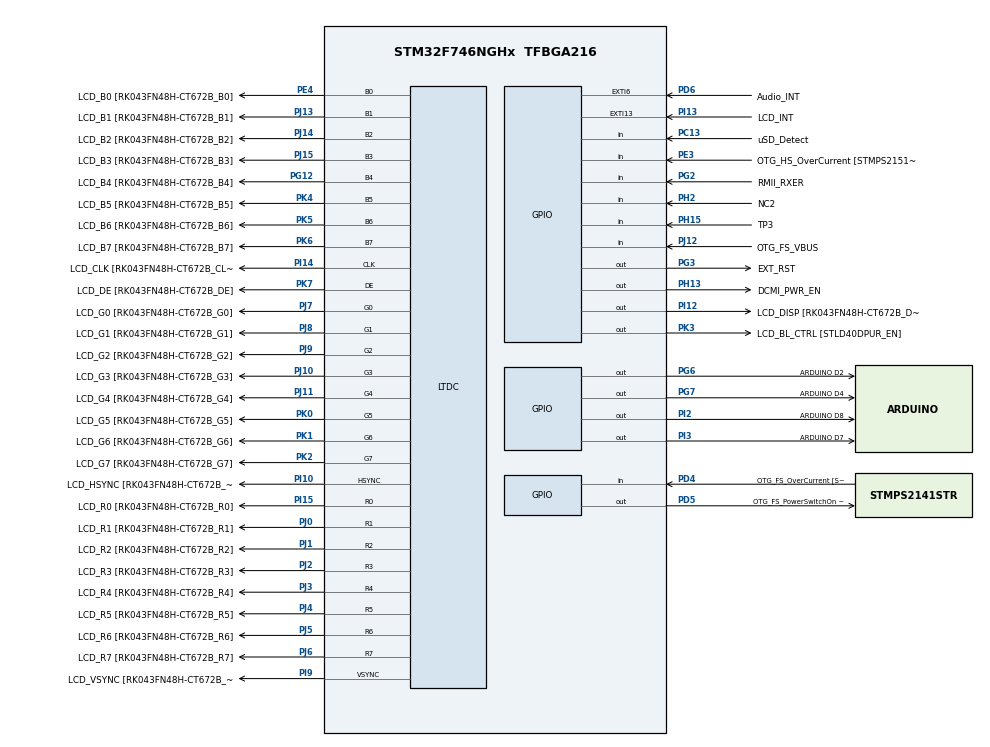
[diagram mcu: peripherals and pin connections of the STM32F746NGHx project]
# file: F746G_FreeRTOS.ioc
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FREERTOS.Tasks01=defaultTask,0,128,StartDefaultTask,Default,NULL
FREERTOS.configUSE_TIMERS=1
Mcu.Family=STM32F7
Mcu.Name=STM32F746NGHx
Mcu.Package=TFBGA216
NVIC.PriorityGroup=NVIC_PRIORITYGROUP_4
NVIC.TIM6_DAC_IRQn=true\:0\:0\:false\:false\:true\:false\:false
NVIC.TimeBase=TIM6_DAC_IRQn
NVIC.TimeBaseIP=TIM6
PA0/WKUP.GPIO_Label=ARDUINO A0
PA0/WKUP.GPIO_Mode=GPIO_MODE_ANALOG
PA0/WKUP.GPIO_PuPd=GPIO_NOPULL
PA0/WKUP.Signal=ADCx_IN0
PA1.GPIO_Label=RMII_REF_CLK [LAN8742A-CZ-TR_REFCLK0]
PA1.Signal=ETH_REF_CLK
PA10.GPIO_Label=OTG_FS_ID
PA10.Signal=USB_OTG_FS_ID
PA11.GPIO_Label=OTG_FS_N
PA11.Signal=USB_OTG_FS_DM
PA12.GPIO_Label=OTG_FS_P
PA12.Signal=USB_OTG_FS_DP
PA13.GPIO_Label=SWDIO
PA13.Signal=SYS_JTMS-SWDIO
PA14.GPIO_Label=SWCLK
PA14.Signal=SYS_JTCK-SWCLK
PA15.GPIO_Label=ARDUINO PWM/D9
PA15.GPIO_ModeDefaultPP=GPIO_MODE_AF_PP
PA15.GPIO_PuPd=GPIO_NOPULL
PA15.GPIO_Speed=GPIO_SPEED_FREQ_LOW
PA15.Signal=S_TIM2_CH1_ETR
PA2.GPIO_Label=RMII_MDIO [LAN8742A-CZ-TR_MDIO]
PA2.Signal=ETH_MDIO
PA3.GPIO_Label=ULPI_D0 [USB3320C-EZK_D0]
PA3.Signal=USB_OTG_HS_ULPI_D0
PA4.GPIO_Label=DCMI_HSYNC
PA4.Signal=DCMI_HSYNC
PA5.GPIO_Label=ULPI_CLK [USB3320C-EZK_CLKOUT]
PA5.Signal=USB_OTG_HS_ULPI_CK
PA6.Signal=DCMI_PIXCLK
PA7.GPIO_Label=RMII_CRS_DV [LAN8742A-CZ-TR_CRS_DV]
PA7.Signal=ETH_CRS_DV
PA8.GPIO_Label=ARDUINO PWM/D10
PA8.GPIO_ModeDefaultPP=GPIO_MODE_AF_PP
PA8.GPIO_PuPd=GPIO_NOPULL
PA8.GPIO_Speed=GPIO_SPEED_FREQ_LOW
PA8.Signal=S_TIM1_CH1
PA9.GPIO_Label=VCP_TX [STM32F103CBT6_PA3]
PA9.GPIO_Mode=GPIO_MODE_AF_PP
PA9.GPIO_PuPd=GPIO_NOPULL
PA9.GPIO_Speed=GPIO_SPEED_FREQ_LOW
PA9.Signal=USART1_TX
PB0.GPIO_Label=ULPI_D1 [USB3320C-EZK_D1]
PB0.Signal=USB_OTG_HS_ULPI_D1
PB1.GPIO_Label=ULPI_D2 [USB3320C-EZK_D2]
PB1.Signal=USB_OTG_HS_ULPI_D2
PB10.GPIO_Label=ULPI_D3 [USB3320C-EZK_D3]
PB10.Signal=USB_OTG_HS_ULPI_D3
PB11.GPIO_Label=ULPI_D4 [USB3320C-EZK_D4]
PB11.Signal=USB_OTG_HS_ULPI_D4
PB12.GPIO_Label=ULPI_D5 [USB3320C-EZK_D5]
PB12.Signal=USB_OTG_HS_ULPI_D5
PB13.GPIO_Label=ULPI_D6 [USB3320C-EZK_D6]
PB13.Signal=USB_OTG_HS_ULPI_D6
PB14.GPIO_Label=ARDUINO MISO/D12
PB14.GPIO_Mode=GPIO_MODE_AF_PP
PB14.GPIO_PuPd=GPIO_NOPULL
PB14.GPIO_Speed=GPIO_SPEED_FREQ_LOW
PB14.Signal=SPI2_MISO
PB15.GPIO_Label=ARDUINO MOSI/PWM/D11
PB15.GPIO_Mode=GPIO_MODE_AF_PP
PB15.GPIO_PuPd=GPIO_NOPULL
PB15.GPIO_Speed=GPIO_SPEED_FREQ_LOW
PB15.Signal=SPI2_MOSI
PB2.Signal=QUADSPI_CLK
PB3.GPIO_Label=SWO
PB3.Signal=SYS_JTDO-SWO
PB4.GPIO_Label=ARDUINO PWM/D3
PB4.GPIO_ModeDefaultPP=GPIO_MODE_AF_PP
PB4.GPIO_PuPd=GPIO_NOPULL
PB4.GPIO_Speed=GPIO_SPEED_FREQ_LOW
PB4.Signal=S_TIM3_CH1
PB5.GPIO_Label=ULPI_D7 [USB3320C-EZK_D7]
PB5.Signal=USB_OTG_HS_ULPI_D7
PB6.GPIO_Label=QSPI_NCS [N25Q128A13EF840E_S]
PB6.Signal=QUADSPI_BK1_NCS
PB7.GPIO_Label=VCP_RX [STM32F103CBT6_PA2]
PB7.GPIO_Mode=GPIO_MODE_AF_PP
PB7.GPIO_PuPd=GPIO_NOPULL
PB7.GPIO_Speed=GPIO_SPEED_FREQ_LOW
PB7.Signal=USART1_RX
PB8.GPIO_Label=ARDUINO SCL/D15
PB8.GPIO_Mode=GPIO_MODE_AF_OD
PB8.GPIO_PuPd=GPIO_NOPULL
PB8.GPIO_Speed=GPIO_SPEED_FREQ_LOW
PB8.Signal=I2C1_SCL
PB9.GPIO_Label=ARDUINO SDA/D14
PB9.GPIO_Mode=GPIO_MODE_AF_OD
PB9.GPIO_PuPd=GPIO_NOPULL
PB9.GPIO_Speed=GPIO_SPEED_FREQ_LOW
PB9.Signal=I2C1_SDA
PC0.GPIO_Label=ULPI_STP [USB3320C-EZK_STP]
PC0.Signal=USB_OTG_HS_ULPI_STP
PC1.GPIO_Label=RMII_MDC [LAN8742A-CZ-TR_MDC]
PC1.Signal=ETH_MDC
PC10.GPIO_Label=SDMMC_D2
PC10.Signal=SDMMC1_D2
PC11.GPIO_Label=SDMMC_D3
PC11.Signal=SDMMC1_D3
PC12.GPIO_Label=SDMMC_CK
PC12.Signal=SDMMC1_CK
PC13.GPIO_Label=uSD_Detect
PC13.Signal=GPIO_Input
PC14/OSC32_IN.GPIO_Label=RCC_OSC32_IN
PC14/OSC32_IN.Signal=RCC_OSC32_IN
PC15/OSC32_OUT.GPIO_Label=RCC_OSC32_OUT
PC15/OSC32_OUT.Signal=RCC_OSC32_OUT
PC2.GPIO_Label=ULPI_DIR [USB3320C-EZK_DIR]
PC2.Signal=USB_OTG_HS_ULPI_DIR
PC3.GPIO_Label=FMC_SDCKE0 [MT48LC4M32B2B5-6A_CKE]
PC3.Signal=FMC_SDCKE0
PC4.GPIO_Label=RMII_RXD0 [LAN8742A-CZ-TR_RXD0]
PC4.Signal=ETH_RXD0
PC5.GPIO_Label=RMII_RXD1 [LAN8742A-CZ-TR_RXD1]
PC5.Signal=ETH_RXD1
PC6.GPIO_Label=ARDUINO TX/D1
PC6.Signal=USART6_TX
PC7.GPIO_Label=ARDUINO RX/D0
PC7.Signal=USART6_RX
PC8.Signal=SDMMC1_D0
PC9.Signal=SDMMC1_D1
PD0.GPIO_Label=FMC_D2 [MT48LC4M32B2B5-6A_DQ2]
PD0.Signal=FMC_D2_DA2
PD1.GPIO_Label=FMC_D3 [MT48LC4M32B2B5-6A_DQ3]
PD1.Signal=FMC_D3_DA3
PD10.GPIO_Label=FMC_D15 [MT48LC4M32B2B5-6A_DQ15]
PD10.Signal=FMC_D15_DA15
PD11.GPIO_Label=QSPI_D0 [N25Q128A13EF840E_DQ0]
PD11.Signal=QUADSPI_BK1_IO0
PD12.GPIO_Label=QSPI_D1 [N25Q128A13EF840E_DQ1]
PD12.Signal=QUADSPI_BK1_IO1
PD13.GPIO_Label=QSPI_D3 [N25Q128A13EF840E_DQ3]
PD13.Signal=QUADSPI_BK1_IO3
PD14.GPIO_Label=FMC_D0 [MT48LC4M32B2B5-6A_DQ0]
PD14.Signal=FMC_D0_DA0
PD15.GPIO_Label=FMC_D1 [MT48LC4M32B2B5-6A_DQ1]
PD15.Signal=FMC_D1_DA1
PD2.GPIO_Label=SDMMC_D0
PD2.Signal=SDMMC1_CMD
PD3.GPIO_Label=DCMI_D5
PD3.Signal=DCMI_D5
PD4.GPIO_Label=OTG_FS_OverCurrent [STMPS2141STR_Fault]
PD4.Signal=GPIO_Input
PD5.GPIO_Label=OTG_FS_PowerSwitchOn [STMPS2141STR_EN]
PD5.PinState=GPIO_PIN_SET
PD5.Signal=GPIO_Output
PD6.GPIO_Label=Audio_INT
PD6.GPIO_ModeDefaultEXTI=GPIO_MODE_EVT_RISING
PD6.Signal=GPXTI6
PD7.GPIO_Label=SPDIF_RX0 [74LVC1G04SE_4]
PD7.Signal=SPDIFRX_IN0
PD8.GPIO_Label=FMC_D13 [MT48LC4M32B2B5-6A_DQ13]
PD8.Signal=FMC_D13_DA13
PD9.GPIO_Label=FMC_D14 [MT48LC4M32B2B5-6A_DQ14]
PD9.Signal=FMC_D14_DA14
PE0.GPIO_Label=FMC_NBL0 [MT48LC4M32B2B5-6A_DQM0]
PE0.Signal=FMC_NBL0
PE1.GPIO_Label=FMC_NBL1 [MT48LC4M32B2B5-6A_DQM1]
PE1.Signal=FMC_NBL1
PE10.GPIO_Label=FMC_D7 [MT48LC4M32B2B5-6A_DQ7]
PE10.Signal=FMC_D7_DA7
PE11.GPIO_Label=FMC_D8 [MT48LC4M32B2B5-6A_DQ8]
PE11.Signal=FMC_D8_DA8
PE12.GPIO_Label=FMC_D9 [MT48LC4M32B2B5-6A_DQ9]
PE12.Signal=FMC_D9_DA9
PE13.GPIO_Label=FMC_D10 [MT48LC4M32B2B5-6A_DQ10]
PE13.Signal=FMC_D10_DA10
PE14.GPIO_Label=FMC_D11 [MT48LC4M32B2B5-6A_DQ11]
PE14.Signal=FMC_D11_DA11
PE15.GPIO_Label=FMC_D12 [MT48LC4M32B2B5-6A_DQ12]
PE15.Signal=FMC_D12_DA12
PE2.GPIO_Label=QSPI_D2 [N25Q128A13EF840E_DQ2]
PE2.Signal=QUADSPI_BK1_IO2
PE3.GPIO_Label=OTG_HS_OverCurrent [STMPS2151STR_FAULT]
PE3.Signal=GPIO_Input
PE4.GPIO_Label=LCD_B0 [RK043FN48H-CT672B_B0]
PE4.Mode=RGB888
PE4.Signal=LTDC_B0
PE5.GPIO_Label=DCMI_D6
PE5.Signal=DCMI_D6
PE6.GPIO_Label=DCMI_D7
PE6.Signal=DCMI_D7
PE7.GPIO_Label=FMC_D4 [MT48LC4M32B2B5-6A_DQ4]
PE7.Signal=FMC_D4_DA4
PE8.GPIO_Label=FMC_D5 [MT48LC4M32B2B5-6A_DQ5]
PE8.Signal=FMC_D5_DA5
PE9.GPIO_Label=FMC_D6 [MT48LC4M32B2B5-6A_DQ6]
PE9.Signal=FMC_D6_DA6
PF0.GPIO_Label=FMC_A0 [MT48LC4M32B2B5-6A_A0]
PF0.Signal=FMC_A0
PF1.GPIO_Label=FMC_A1 [MT48LC4M32B2B5-6A_A1]
PF1.Signal=FMC_A1
PF10.GPIO_Label=ARDUINO A1
PF10.GPIO_Mode=GPIO_MODE_ANALOG
PF10.GPIO_PuPd=GPIO_NOPULL
PF10.Signal=ADC3_IN8
PF11.GPIO_Label=FMC_SDNRAS [MT48LC4M32B2B5-6A_RAS]
PF11.Signal=FMC_SDNRAS
PF12.GPIO_Label=FMC_A6 [MT48LC4M32B2B5-6A_A6]
PF12.Signal=FMC_A6
PF13.GPIO_Label=FMC_A7 [MT48LC4M32B2B5-6A_A7]
PF13.Signal=FMC_A7
PF14.GPIO_Label=FMC_A8 [MT48LC4M32B2B5-6A_A8]
PF14.Signal=FMC_A8
PF15.GPIO_Label=FMC_A9 [MT48LC4M32B2B5-6A_A9]
PF15.Signal=FMC_A9
PF2.GPIO_Label=FMC_A2 [MT48LC4M32B2B5-6A_A2]
PF2.Signal=FMC_A2
PF3.GPIO_Label=FMC_A3 [MT48LC4M32B2B5-6A_A3]
PF3.Signal=FMC_A3
PF4.GPIO_Label=FMC_A4 [MT48LC4M32B2B5-6A_A4]
PF4.Signal=FMC_A4
PF5.GPIO_Label=FMC_A5 [MT48LC4M32B2B5-6A_A5]
PF5.Signal=FMC_A5
PF6.GPIO_Label=ARDUINO A5
PF6.GPIO_Mode=GPIO_MODE_ANALOG
PF6.GPIO_PuPd=GPIO_NOPULL
PF6.Signal=ADC3_IN4
PF7.GPIO_Label=ARDUINO A4
PF7.GPIO_Mode=GPIO_MODE_ANALOG
PF7.GPIO_PuPd=GPIO_NOPULL
PF7.Signal=ADC3_IN5
PF8.GPIO_Label=ARDUINO A3
PF8.GPIO_Mode=GPIO_MODE_ANALOG
PF8.GPIO_PuPd=GPIO_NOPULL
PF8.Signal=ADC3_IN6
PF9.GPIO_Label=ARDUINO A2
PF9.GPIO_Mode=GPIO_MODE_ANALOG
PF9.GPIO_PuPd=GPIO_NOPULL
PF9.Signal=ADC3_IN7
PG0.GPIO_Label=FMC_A10 [MT48LC4M32B2B5-6A_A10]
PG0.Signal=FMC_A10
PG1.GPIO_Label=FMC_A11 [MT48LC4M32B2B5-6A_A11]
PG1.Signal=FMC_A11
PG10.GPIO_Label=SAI2_SDB [WM8994ECS/R_ADCDAT1]
PG10.Signal=SAI2_SD_B
PG11.GPIO_Label=RMII_TX_EN [LAN8742A-CZ-TR_TXEN]
PG11.Signal=ETH_TX_EN
PG12.GPIO_Label=LCD_B4 [RK043FN48H-CT672B_B4]
PG12.Mode=RGB888
PG12.Signal=LTDC_B4
PG13.GPIO_Label=RMII_TXD0 [LAN8742A-CZ-TR_TXD0]
PG13.Signal=ETH_TXD0
PG14.GPIO_Label=RMII_TXD1 [LAN8742A-CZ-TR_TXD1]
PG14.Signal=ETH_TXD1
PG15.GPIO_Label=FMC_SDNCAS [MT48LC4M32B2B5-6A_CAS]
PG15.Signal=FMC_SDNCAS
PG2.GPIO_Label=RMII_RXER
PG2.Signal=GPIO_Input
PG3.GPIO_Label=EXT_RST
PG3.Signal=GPIO_Output
PG4.GPIO_Label=FMC_BA0 [MT48LC4M32B2B5-6A_BA0]
PG4.Signal=FMC_A14_BA0
PG5.GPIO_Label=FMC_BA1 [MT48LC4M32B2B5-6A_BA1]
PG5.Signal=FMC_A15_BA1
PG6.GPIO_Label=ARDUINO D2
PG6.Signal=GPIO_Output
PG7.GPIO_Label=ARDUINO D4
PG7.Signal=GPIO_Output
PG8.GPIO_Label=FMC_SDCLK [MT48LC4M32B2B5-6A_CLK]
PG8.Signal=FMC_SDCLK
PG9.GPIO_Label=DCMI_VSYNC
PG9.Signal=DCMI_VSYNC
PH0/OSC_IN.GPIO_Label=OSC_25M [NZ2520SB-25.00M_OUT]
PH0/OSC_IN.Signal=RCC_OSC_IN
PH1/OSC_OUT.Signal=RCC_OSC_OUT
PH10.GPIO_Label=DCMI_D1
PH10.Signal=DCMI_D1
PH11.GPIO_Label=DCMI_D2
PH11.Signal=DCMI_D2
PH12.GPIO_Label=DCMI_D3
PH12.Signal=DCMI_D3
PH13.GPIO_Label=DCMI_PWR_EN
PH13.Signal=GPIO_Output
PH14.GPIO_Label=DCMI_D4
PH14.Signal=DCMI_D4
PH15.GPIO_Label=TP3
PH15.Signal=GPIO_Input
PH2.GPIO_Label=NC2
PH2.Signal=GPIO_Input
PH3.GPIO_Label=FMC_SDNE0 [MT48LC4M32B2B5-6A_CS]
PH3.Signal=FMC_SDNE0
PH4.GPIO_Label=ULPI_NXT [USB3320C-EZK_NXT]
PH4.Signal=USB_OTG_HS_ULPI_NXT
PH5.GPIO_Label=FMC_SDNME [MT48LC4M32B2B5-6A_WE]
PH5.Signal=FMC_SDNWE
PH6.GPIO_Label=ARDUINO PWM/D6
PH6.Signal=S_TIM12_CH1
PH7.GPIO_Label=LCD_SCL [RK043FN48H-CT672B_SCL]
PH7.Signal=I2C3_SCL
PH8.GPIO_Label=LCD_SDA [RK043FN48H-CT672B_SDA]
PH8.Signal=I2C3_SDA
PH9.GPIO_Label=DCMI_D0
PH9.Signal=DCMI_D0
PI0.GPIO_Label=ARDUINO PWM/CS/D5
PI0.GPIO_ModeDefaultPP=GPIO_MODE_AF_PP
PI0.GPIO_PuPd=GPIO_NOPULL
PI0.GPIO_Speed=GPIO_SPEED_FREQ_LOW
PI0.Signal=S_TIM5_CH4
PI1.GPIO_Label=ARDUINO SCK/D13
PI1.GPIO_Mode=GPIO_MODE_AF_PP
PI1.GPIO_PuPd=GPIO_NOPULL
PI1.GPIO_Speed=GPIO_SPEED_FREQ_LOW
PI1.Signal=SPI2_SCK
PI10.GPIO_Label=LCD_HSYNC [RK043FN48H-CT672B_HSYNC]
PI10.Mode=RGB888
PI10.Signal=LTDC_HSYNC
PI12.GPIO_Label=LCD_DISP [RK043FN48H-CT672B_DISP] 
PI12.Signal=GPIO_Output
PI13.GPIO_Label=LCD_INT
PI13.GPIO_ModeDefaultEXTI=GPIO_MODE_EVT_RISING
PI13.Signal=GPXTI13
PI14.GPIO_Label=LCD_CLK [RK043FN48H-CT672B_CLK]
PI14.Mode=RGB888
PI14.Signal=LTDC_CLK
PI15.GPIO_Label=LCD_R0 [RK043FN48H-CT672B_R0]
PI15.Mode=RGB888
PI15.Signal=LTDC_R0
PI2.GPIO_Label=ARDUINO D8
PI2.Signal=GPIO_Output
PI3.GPIO_Label=ARDUINO D7
PI3.Signal=GPIO_Output
PI4.GPIO_Label=SAI2_MCLKA [WM8994ECS/R_MCLK1]
PI4.Signal=SAI2_MCLK_A
PI5.GPIO_Label=SAI2_SCKA [WM8994ECS/R_BCLK1]
PI5.Signal=SAI2_SCK_A
PI6.GPIO_Label=SAI2_SDA [WM8994ECS/R_DACDAT1]
PI6.Signal=SAI2_SD_A
PI7.GPIO_Label=SAI2_FSA [WM8994ECS/R_LRCLK1]
PI7.Signal=SAI2_FS_A
PI8.GPIO_Label=NC1 [TP2]
PI8.Signal=RTC_TS
PI9.GPIO_Label=LCD_VSYNC [RK043FN48H-CT672B_VSYNC]
PI9.Mode=RGB888
PI9.Signal=LTDC_VSYNC
PJ0.GPIO_Label=LCD_R1 [RK043FN48H-CT672B_R1]
PJ0.Mode=RGB888
PJ0.Signal=LTDC_R1
PJ1.GPIO_Label=LCD_R2 [RK043FN48H-CT672B_R2]
PJ1.Mode=RGB888
PJ1.Signal=LTDC_R2
PJ10.GPIO_Label=LCD_G3 [RK043FN48H-CT672B_G3]
PJ10.Mode=RGB888
PJ10.Signal=LTDC_G3
PJ11.GPIO_Label=LCD_G4 [RK043FN48H-CT672B_G4]
PJ11.Mode=RGB888
PJ11.Signal=LTDC_G4
PJ12.GPIO_Label=OTG_FS_VBUS
PJ12.Signal=GPIO_Input
PJ13.GPIO_Label=LCD_B1 [RK043FN48H-CT672B_B1]
PJ13.Mode=RGB888
PJ13.Signal=LTDC_B1
PJ14.GPIO_Label=LCD_B2 [RK043FN48H-CT672B_B2]
PJ14.Mode=RGB888
PJ14.Signal=LTDC_B2
PJ15.GPIO_Label=LCD_B3 [RK043FN48H-CT672B_B3]
PJ15.Mode=RGB888
PJ15.Signal=LTDC_B3
PJ2.GPIO_Label=LCD_R3 [RK043FN48H-CT672B_R3]
PJ2.Mode=RGB888
PJ2.Signal=LTDC_R3
PJ3.GPIO_Label=LCD_R4 [RK043FN48H-CT672B_R4]
PJ3.Mode=RGB888
PJ3.Signal=LTDC_R4
PJ4.GPIO_Label=LCD_R5 [RK043FN48H-CT672B_R5]
PJ4.Mode=RGB888
PJ4.Signal=LTDC_R5
PJ5.GPIO_Label=LCD_R6 [RK043FN48H-CT672B_R6]
PJ5.Mode=RGB888
PJ5.Signal=LTDC_R6
PJ6.GPIO_Label=LCD_R7 [RK043FN48H-CT672B_R7]
PJ6.Mode=RGB888
PJ6.Signal=LTDC_R7
PJ7.GPIO_Label=LCD_G0 [RK043FN48H-CT672B_G0]
PJ7.Mode=RGB888
PJ7.Signal=LTDC_G0
PJ8.GPIO_Label=LCD_G1 [RK043FN48H-CT672B_G1]
PJ8.Mode=RGB888
PJ8.Signal=LTDC_G1
PJ9.GPIO_Label=LCD_G2 [RK043FN48H-CT672B_G2]
PJ9.Mode=RGB888
PJ9.Signal=LTDC_G2
PK0.GPIO_Label=LCD_G5 [RK043FN48H-CT672B_G5]
PK0.Mode=RGB888
PK0.Signal=LTDC_G5
PK1.GPIO_Label=LCD_G6 [RK043FN48H-CT672B_G6]
PK1.Mode=RGB888
PK1.Signal=LTDC_G6
PK2.GPIO_Label=LCD_G7 [RK043FN48H-CT672B_G7]
PK2.Mode=RGB888
PK2.Signal=LTDC_G7
PK3.GPIO_Label=LCD_BL_CTRL [STLD40DPUR_EN]
PK3.Signal=GPIO_Output
PK4.GPIO_Label=LCD_B5 [RK043FN48H-CT672B_B5]
PK4.Mode=RGB888
PK4.Signal=LTDC_B5
PK5.GPIO_Label=LCD_B6 [RK043FN48H-CT672B_B6]
PK5.Mode=RGB888
PK5.Signal=LTDC_B6
PK6.GPIO_Label=LCD_B7 [RK043FN48H-CT672B_B7]
PK6.Mode=RGB888
PK6.Signal=LTDC_B7
PK7.GPIO_Label=LCD_DE [RK043FN48H-CT672B_DE]
PK7.Mode=RGB888
PK7.Signal=LTDC_DE
ProjectManager.HeapSize=0x200
ProjectManager.StackSize=0x400
ProjectManager.TargetToolchain=TrueSTUDIO
RCC.AHBFreq_Value=200000000
RCC.APB1CLKDivider=RCC_HCLK_DIV4
RCC.APB1Freq_Value=50000000
RCC.APB1TimFreq_Value=100000000
RCC.APB2CLKDivider=RCC_HCLK_DIV2
RCC.APB2Freq_Value=100000000
RCC.APB2TimFreq_Value=200000000
RCC.CortexFreq_Value=200000000
RCC.HCLKFreq_Value=200000000
RCC.HSE_VALUE=25000000
RCC.HSI_VALUE=16000000
RCC.LSE_VALUE=32768
RCC.PLLM=8
RCC.PLLN=200
RCC.PLLSourceVirtual=RCC_PLLSOURCE_HSI
RCC.SYSCLKFreq_VALUE=200000000
RCC.SYSCLKSource=RCC_SYSCLKSOURCE_PLLCLK
RCC.USBFreq_Value=200000000
RCC.VCOOutputFreq_Value=400000000
SH.ADCx_IN0.0=ADC3_IN0
SH.FMC_A0.0=FMC_A0
SH.FMC_A1.0=FMC_A1
SH.FMC_A10.0=FMC_A10
SH.FMC_A11.0=FMC_A11
SH.FMC_A14_BA0.0=FMC_BA0
SH.FMC_A15_BA1.0=FMC_BA1
SH.FMC_A2.0=FMC_A2
SH.FMC_A3.0=FMC_A3
SH.FMC_A4.0=FMC_A4
SH.FMC_A5.0=FMC_A5
SH.FMC_A6.0=FMC_A6
SH.FMC_A7.0=FMC_A7
SH.FMC_A8.0=FMC_A8
SH.FMC_A9.0=FMC_A9
SH.FMC_D0_DA0.0=FMC_D0
SH.FMC_D10_DA10.0=FMC_D10
SH.FMC_D11_DA11.0=FMC_D11
SH.FMC_D12_DA12.0=FMC_D12
SH.FMC_D13_DA13.0=FMC_D13
SH.FMC_D14_DA14.0=FMC_D14
SH.FMC_D15_DA15.0=FMC_D15
SH.FMC_D1_DA1.0=FMC_D1
SH.FMC_D2_DA2.0=FMC_D2
SH.FMC_D3_DA3.0=FMC_D3
SH.FMC_D4_DA4.0=FMC_D4
SH.FMC_D5_DA5.0=FMC_D5
SH.FMC_D6_DA6.0=FMC_D6
SH.FMC_D7_DA7.0=FMC_D7
SH.FMC_D8_DA8.0=FMC_D8
SH.FMC_D9_DA9.0=FMC_D9
SH.FMC_NBL0.0=FMC_NBL0
SH.FMC_NBL1.0=FMC_NBL1
SH.FMC_SDCLK.0=FMC_SDCLK
SH.FMC_SDNCAS.0=FMC_SDNCAS
SH.FMC_SDNRAS.0=FMC_SDNRAS
SH.FMC_SDNWE.0=FMC_SDNWE
SH.S_TIM12_CH1.0=TIM12_CH1
SH.S_TIM1_CH1.0=TIM1_CH1
SH.S_TIM2_CH1_ETR.0=TIM2_CH1
SH.S_TIM3_CH1.0=TIM3_CH1
SH.S_TIM5_CH4.0=TIM5_CH4
VP_FREERTOS_VS_ENABLE.Mode=Enabled
VP_SYS_VS_tim6.Mode=TIM6
board=32F746GDISCOVERY

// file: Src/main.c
/* USER CODE BEGIN Header */
/**
  ******************************************************************************
  * @file           : main.c
  * @brief          : Main program body
  ******************************************************************************
  * This notice applies to any and all portions of this file
  * that are not between comment pairs USER CODE BEGIN and
  * USER CODE END. Other portions of this file, whether
  * inserted by the user or by software development tools
  * are owned by their respective copyright owners.
  *
  * Copyright (c) 2019 STMicroelectronics International N.V.
  * All rights reserved.
  *
  * Redistribution and use in source and binary forms, with or without
  * modification, are permitted, provided that the following conditions are met:
  *
  * 1. Redistribution of source code must retain the above copyright notice,
  *    this list of conditions and the following disclaimer.
  * 2. Redistributions in binary form must reproduce the above copyright notice,
  *    this list of conditions and the following disclaimer in the documentation
  *    and/or other materials provided with the distribution.
  * 3. Neither the name of STMicroelectronics nor the names of other
  *    contributors to this software may be used to endorse or promote products
  *    derived from this software without specific written permission.
  * 4. This software, including modifications and/or derivative works of this
  *    software, must execute solely and exclusively on microcontroller or
  *    microprocessor devices manufactured by or for STMicroelectronics.
  * 5. Redistribution and use of this software other than as permitted under
  *    this license is void and will automatically terminate your rights under
  *    this license.
  *
  * THIS SOFTWARE IS PROVIDED BY STMICROELECTRONICS AND CONTRIBUTORS "AS IS"
  * AND ANY EXPRESS, IMPLIED OR STATUTORY WARRANTIES, INCLUDING, BUT NOT
  * LIMITED TO, THE IMPLIED WARRANTIES OF MERCHANTABILITY, FITNESS FOR A
  * PARTICULAR PURPOSE AND NON-INFRINGEMENT OF THIRD PARTY INTELLECTUAL PROPERTY
  * RIGHTS ARE DISCLAIMED TO THE FULLEST EXTENT PERMITTED BY LAW. IN NO EVENT
  * SHALL STMICROELECTRONICS OR CONTRIBUTORS BE LIABLE FOR ANY DIRECT, INDIRECT,
  * INCIDENTAL, SPECIAL, EXEMPLARY, OR CONSEQUENTIAL DAMAGES (INCLUDING, BUT NOT
  * LIMITED TO, PROCUREMENT OF SUBSTITUTE GOODS OR SERVICES; LOSS OF USE, DATA,
  * OR PROFITS; OR BUSINESS INTERRUPTION) HOWEVER CAUSED AND ON ANY THEORY OF
  * LIABILITY, WHETHER IN CONTRACT, STRICT LIABILITY, OR TORT (INCLUDING
  * NEGLIGENCE OR OTHERWISE) ARISING IN ANY WAY OUT OF THE USE OF THIS SOFTWARE,
  * EVEN IF ADVISED OF THE POSSIBILITY OF SUCH DAMAGE.
  *
  ******************************************************************************
  */
/* USER CODE END Header */

#include "main.h"
#include "cmsis_os.h"
#include "gpio.h"

void SystemClock_Config(void);
void MX_FREERTOS_Init(void);

int main(void)
{

  /* MCU Configuration--------------------------------------------------------*/

  /* Reset of all peripherals, Initializes the Flash interface and the Systick. */
  HAL_Init();

  /* Configure the system clock */
  SystemClock_Config();

  /* Initialize all configured peripherals */
  MX_GPIO_Init();

  /* Call init function for freertos objects (in freertos.c) */
  MX_FREERTOS_Init();

  /* Start scheduler */
  osKernelStart();

  /* We should never get here as control is now taken by the scheduler */

  /* Infinite loop */
  while (1)
  {

  }
}

void SystemClock_Config(void)
{
  RCC_OscInitTypeDef RCC_OscInitStruct = {0};
  RCC_ClkInitTypeDef RCC_ClkInitStruct = {0};

  /**Configure the main internal regulator output voltage
  */
  __HAL_RCC_PWR_CLK_ENABLE();
  __HAL_PWR_VOLTAGESCALING_CONFIG(PWR_REGULATOR_VOLTAGE_SCALE2);
  /**Initializes the CPU, AHB and APB busses clocks
  */
  RCC_OscInitStruct.OscillatorType = RCC_OSCILLATORTYPE_HSI;
  RCC_OscInitStruct.HSIState = RCC_HSI_ON;
  RCC_OscInitStruct.HSICalibrationValue = RCC_HSICALIBRATION_DEFAULT;
  RCC_OscInitStruct.PLL.PLLState = RCC_PLL_ON;
  RCC_OscInitStruct.PLL.PLLSource = RCC_PLLSOURCE_HSI;
  RCC_OscInitStruct.PLL.PLLM = 10;
  RCC_OscInitStruct.PLL.PLLN = 210;
  RCC_OscInitStruct.PLL.PLLP = RCC_PLLP_DIV2;
  RCC_OscInitStruct.PLL.PLLQ = 2;
  if (HAL_RCC_OscConfig(&RCC_OscInitStruct) != HAL_OK)
  {
    Error_Handler();
  }
  /**Initializes the CPU, AHB and APB busses clocks
  */
  RCC_ClkInitStruct.ClockType = RCC_CLOCKTYPE_HCLK|RCC_CLOCKTYPE_SYSCLK
                              |RCC_CLOCKTYPE_PCLK1|RCC_CLOCKTYPE_PCLK2;
  RCC_ClkInitStruct.SYSCLKSource = RCC_SYSCLKSOURCE_PLLCLK;
  RCC_ClkInitStruct.AHBCLKDivider = RCC_SYSCLK_DIV1;
  RCC_ClkInitStruct.APB1CLKDivider = RCC_HCLK_DIV4;
  RCC_ClkInitStruct.APB2CLKDivider = RCC_HCLK_DIV2;

  if (HAL_RCC_ClockConfig(&RCC_ClkInitStruct, FLASH_LATENCY_5) != HAL_OK)
  {
    Error_Handler();
  }
}

void HAL_TIM_PeriodElapsedCallback(TIM_HandleTypeDef *htim)
{
  if (htim->Instance == TIM6) {
    HAL_IncTick();
  }
}

void Error_Handler(void)
{
}

/************************ (C) COPYRIGHT STMicroelectronics *****END OF FILE****/
